VERSION 5.7 ;
  NOWIREEXTENSIONATPIN ON ;
  DIVIDERCHAR "/" ;
  BUSBITCHARS "[]" ;
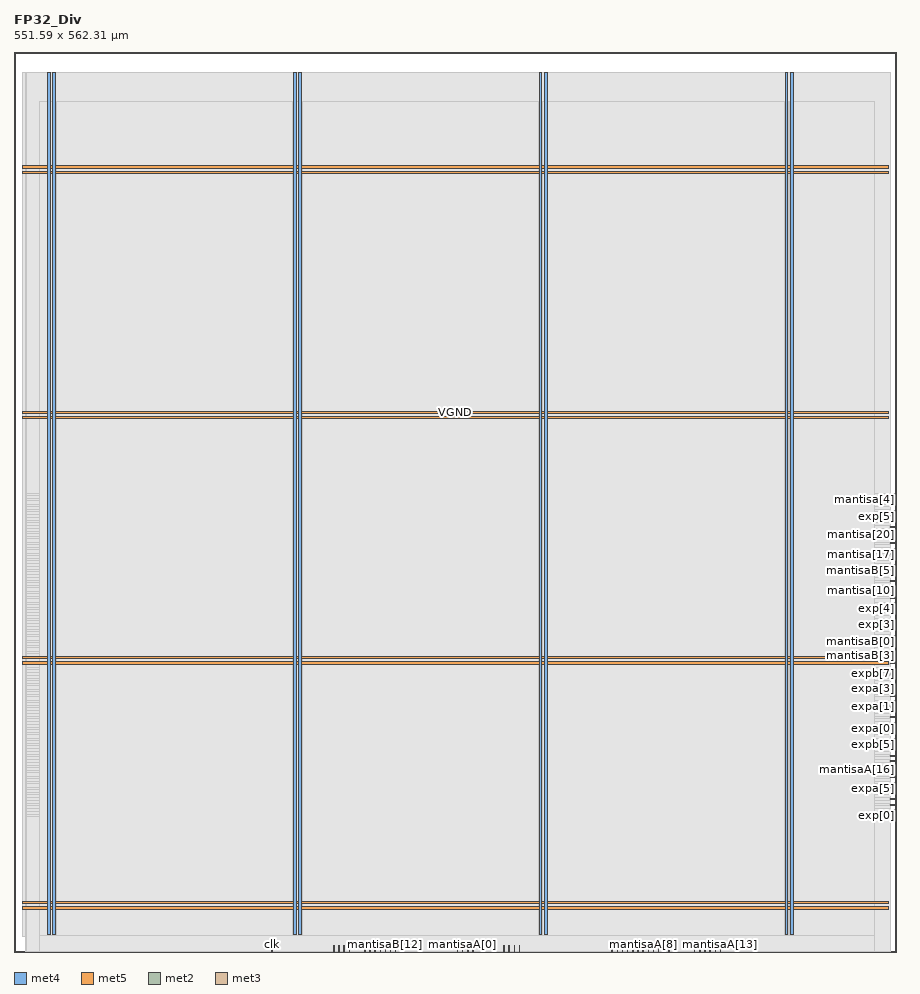
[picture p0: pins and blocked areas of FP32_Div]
MACRO FP32_Div
  CLASS BLOCK ;
  FOREIGN FP32_Div ;
  ORIGIN 0.000 0.000 ;
  SIZE 551.590 BY 562.310 ;
  PIN VGND
    DIRECTION INOUT ;
    USE GROUND ;
    PORT
      LAYER met4 ;
        RECT 24.340 10.640 25.940 549.680 ;
    END
    PORT
      LAYER met4 ;
        RECT 177.940 10.640 179.540 549.680 ;
    END
    PORT
      LAYER met4 ;
        RECT 331.540 10.640 333.140 549.680 ;
    END
    PORT
      LAYER met4 ;
        RECT 485.140 10.640 486.740 549.680 ;
    END
    PORT
      LAYER met5 ;
        RECT 5.280 30.030 546.260 31.630 ;
    END
    PORT
      LAYER met5 ;
        RECT 5.280 183.210 546.260 184.810 ;
    END
    PORT
      LAYER met5 ;
        RECT 5.280 336.390 546.260 337.990 ;
    END
    PORT
      LAYER met5 ;
        RECT 5.280 489.570 546.260 491.170 ;
    END
  END VGND
  PIN VPWR
    DIRECTION INOUT ;
    USE POWER ;
    PORT
      LAYER met4 ;
        RECT 21.040 10.640 22.640 549.680 ;
    END
    PORT
      LAYER met4 ;
        RECT 174.640 10.640 176.240 549.680 ;
    END
    PORT
      LAYER met4 ;
        RECT 328.240 10.640 329.840 549.680 ;
    END
    PORT
      LAYER met4 ;
        RECT 481.840 10.640 483.440 549.680 ;
    END
    PORT
      LAYER met5 ;
        RECT 5.280 26.730 546.260 28.330 ;
    END
    PORT
      LAYER met5 ;
        RECT 5.280 179.910 546.260 181.510 ;
    END
    PORT
      LAYER met5 ;
        RECT 5.280 333.090 546.260 334.690 ;
    END
    PORT
      LAYER met5 ;
        RECT 5.280 486.270 546.260 487.870 ;
    END
  END VPWR
  PIN clk
    DIRECTION INPUT ;
    USE SIGNAL ;
    ANTENNAGATEAREA 1.286700 ;
    ANTENNADIFFAREA 0.434700 ;
    PORT
      LAYER met2 ;
        RECT 161.090 0.000 161.370 4.000 ;
    END
  END clk
  PIN exp[0]
    DIRECTION OUTPUT ;
    USE SIGNAL ;
    ANTENNADIFFAREA 0.445500 ;
    PORT
      LAYER met3 ;
        RECT 547.590 85.040 551.590 85.640 ;
    END
  END exp[0]
  PIN exp[1]
    DIRECTION OUTPUT ;
    USE SIGNAL ;
    ANTENNADIFFAREA 0.445500 ;
    PORT
      LAYER met3 ;
        RECT 547.590 95.240 551.590 95.840 ;
    END
  END exp[1]
  PIN exp[2]
    DIRECTION OUTPUT ;
    USE SIGNAL ;
    ANTENNADIFFAREA 0.445500 ;
    PORT
      LAYER met3 ;
        RECT 547.590 285.640 551.590 286.240 ;
    END
  END exp[2]
  PIN exp[3]
    DIRECTION OUTPUT ;
    USE SIGNAL ;
    ANTENNADIFFAREA 0.445500 ;
    PORT
      LAYER met3 ;
        RECT 547.590 204.040 551.590 204.640 ;
    END
  END exp[3]
  PIN exp[4]
    DIRECTION OUTPUT ;
    USE SIGNAL ;
    ANTENNADIFFAREA 0.445500 ;
    PORT
      LAYER met3 ;
        RECT 547.590 214.240 551.590 214.840 ;
    END
  END exp[4]
  PIN exp[5]
    DIRECTION OUTPUT ;
    USE SIGNAL ;
    ANTENNADIFFAREA 0.445500 ;
    PORT
      LAYER met3 ;
        RECT 547.590 272.040 551.590 272.640 ;
    END
  END exp[5]
  PIN exp[6]
    DIRECTION OUTPUT ;
    USE SIGNAL ;
    ANTENNADIFFAREA 0.445500 ;
    PORT
      LAYER met3 ;
        RECT 547.590 258.440 551.590 259.040 ;
    END
  END exp[6]
  PIN exp[7]
    DIRECTION OUTPUT ;
    USE SIGNAL ;
    ANTENNADIFFAREA 0.445500 ;
    PORT
      LAYER met3 ;
        RECT 547.590 268.640 551.590 269.240 ;
    END
  END exp[7]
  PIN expa[0]
    DIRECTION INPUT ;
    USE SIGNAL ;
    ANTENNAGATEAREA 0.196500 ;
    PORT
      LAYER met3 ;
        RECT 547.590 139.440 551.590 140.040 ;
    END
  END expa[0]
  PIN expa[1]
    DIRECTION INPUT ;
    USE SIGNAL ;
    ANTENNAGATEAREA 0.196500 ;
    PORT
      LAYER met3 ;
        RECT 547.590 153.040 551.590 153.640 ;
    END
  END expa[1]
  PIN expa[2]
    DIRECTION INPUT ;
    USE SIGNAL ;
    ANTENNAGATEAREA 0.196500 ;
    PORT
      LAYER met3 ;
        RECT 547.590 149.640 551.590 150.240 ;
    END
  END expa[2]
  PIN expa[3]
    DIRECTION INPUT ;
    USE SIGNAL ;
    ANTENNAGATEAREA 0.126000 ;
    PORT
      LAYER met3 ;
        RECT 547.590 159.840 551.590 160.440 ;
    END
  END expa[3]
  PIN expa[4]
    DIRECTION INPUT ;
    USE SIGNAL ;
    ANTENNAGATEAREA 0.196500 ;
    PORT
      LAYER met3 ;
        RECT 547.590 105.440 551.590 106.040 ;
    END
  END expa[4]
  PIN expa[5]
    DIRECTION INPUT ;
    USE SIGNAL ;
    ANTENNAGATEAREA 0.126000 ;
    PORT
      LAYER met3 ;
        RECT 547.590 102.040 551.590 102.640 ;
    END
  END expa[5]
  PIN expa[6]
    DIRECTION INPUT ;
    USE SIGNAL ;
    ANTENNAGATEAREA 0.196500 ;
    PORT
      LAYER met3 ;
        RECT 547.590 98.640 551.590 99.240 ;
    END
  END expa[6]
  PIN expa[7]
    DIRECTION INPUT ;
    USE SIGNAL ;
    ANTENNAGATEAREA 0.196500 ;
    PORT
      LAYER met3 ;
        RECT 547.590 122.440 551.590 123.040 ;
    END
  END expa[7]
  PIN expb[0]
    DIRECTION INPUT ;
    USE SIGNAL ;
    ANTENNAGATEAREA 0.196500 ;
    PORT
      LAYER met3 ;
        RECT 547.590 156.440 551.590 157.040 ;
    END
  END expb[0]
  PIN expb[1]
    DIRECTION INPUT ;
    USE SIGNAL ;
    ANTENNAGATEAREA 0.196500 ;
    PORT
      LAYER met3 ;
        RECT 547.590 146.240 551.590 146.840 ;
    END
  END expb[1]
  PIN expb[2]
    DIRECTION INPUT ;
    USE SIGNAL ;
    ANTENNAGATEAREA 0.196500 ;
    PORT
      LAYER met3 ;
        RECT 547.590 142.840 551.590 143.440 ;
    END
  END expb[2]
  PIN expb[3]
    DIRECTION INPUT ;
    USE SIGNAL ;
    ANTENNAGATEAREA 0.126000 ;
    PORT
      LAYER met3 ;
        RECT 547.590 132.640 551.590 133.240 ;
    END
  END expb[3]
  PIN expb[4]
    DIRECTION INPUT ;
    USE SIGNAL ;
    ANTENNAGATEAREA 0.196500 ;
    PORT
      LAYER met3 ;
        RECT 547.590 163.240 551.590 163.840 ;
    END
  END expb[4]
  PIN expb[5]
    DIRECTION INPUT ;
    USE SIGNAL ;
    ANTENNAGATEAREA 0.196500 ;
    PORT
      LAYER met3 ;
        RECT 547.590 129.240 551.590 129.840 ;
    END
  END expb[5]
  PIN expb[6]
    DIRECTION INPUT ;
    USE SIGNAL ;
    ANTENNAGATEAREA 0.196500 ;
    PORT
      LAYER met3 ;
        RECT 547.590 125.840 551.590 126.440 ;
    END
  END expb[6]
  PIN expb[7]
    DIRECTION INPUT ;
    USE SIGNAL ;
    ANTENNAGATEAREA 0.196500 ;
    PORT
      LAYER met3 ;
        RECT 547.590 173.440 551.590 174.040 ;
    END
  END expb[7]
  PIN mantisaA[0]
    DIRECTION INPUT ;
    USE SIGNAL ;
    ANTENNAGATEAREA 0.196500 ;
    PORT
      LAYER met2 ;
        RECT 280.230 0.000 280.510 4.000 ;
    END
  END mantisaA[0]
  PIN mantisaA[10]
    DIRECTION INPUT ;
    USE SIGNAL ;
    ANTENNAGATEAREA 0.196500 ;
    PORT
      LAYER met2 ;
        RECT 402.590 0.000 402.870 4.000 ;
    END
  END mantisaA[10]
  PIN mantisaA[11]
    DIRECTION INPUT ;
    USE SIGNAL ;
    ANTENNAGATEAREA 0.196500 ;
    PORT
      LAYER met2 ;
        RECT 396.150 0.000 396.430 4.000 ;
    END
  END mantisaA[11]
  PIN mantisaA[12]
    DIRECTION INPUT ;
    USE SIGNAL ;
    ANTENNAGATEAREA 0.196500 ;
    PORT
      LAYER met2 ;
        RECT 431.570 0.000 431.850 4.000 ;
    END
  END mantisaA[12]
  PIN mantisaA[13]
    DIRECTION INPUT ;
    USE SIGNAL ;
    ANTENNAGATEAREA 0.196500 ;
    PORT
      LAYER met2 ;
        RECT 441.230 0.000 441.510 4.000 ;
    END
  END mantisaA[13]
  PIN mantisaA[14]
    DIRECTION INPUT ;
    USE SIGNAL ;
    ANTENNAGATEAREA 0.196500 ;
    PORT
      LAYER met2 ;
        RECT 434.790 0.000 435.070 4.000 ;
    END
  END mantisaA[14]
  PIN mantisaA[15]
    DIRECTION INPUT ;
    USE SIGNAL ;
    ANTENNAGATEAREA 0.196500 ;
    PORT
      LAYER met2 ;
        RECT 438.010 0.000 438.290 4.000 ;
    END
  END mantisaA[15]
  PIN mantisaA[16]
    DIRECTION INPUT ;
    USE SIGNAL ;
    ANTENNAGATEAREA 0.196500 ;
    PORT
      LAYER met3 ;
        RECT 547.590 108.840 551.590 109.440 ;
    END
  END mantisaA[16]
  PIN mantisaA[17]
    DIRECTION INPUT ;
    USE SIGNAL ;
    ANTENNAGATEAREA 0.196500 ;
    PORT
      LAYER met3 ;
        RECT 547.590 112.240 551.590 112.840 ;
    END
  END mantisaA[17]
  PIN mantisaA[18]
    DIRECTION INPUT ;
    USE SIGNAL ;
    ANTENNAGATEAREA 0.196500 ;
    PORT
      LAYER met3 ;
        RECT 547.590 119.040 551.590 119.640 ;
    END
  END mantisaA[18]
  PIN mantisaA[19]
    DIRECTION INPUT ;
    USE SIGNAL ;
    ANTENNAGATEAREA 0.196500 ;
    PORT
      LAYER met3 ;
        RECT 547.590 115.640 551.590 116.240 ;
    END
  END mantisaA[19]
  PIN mantisaA[1]
    DIRECTION INPUT ;
    USE SIGNAL ;
    ANTENNAGATEAREA 0.196500 ;
    PORT
      LAYER met2 ;
        RECT 277.010 0.000 277.290 4.000 ;
    END
  END mantisaA[1]
  PIN mantisaA[20]
    DIRECTION INPUT ;
    USE SIGNAL ;
    ANTENNAGATEAREA 0.196500 ;
    PORT
      LAYER met2 ;
        RECT 428.350 0.000 428.630 4.000 ;
    END
  END mantisaA[20]
  PIN mantisaA[21]
    DIRECTION INPUT ;
    USE SIGNAL ;
    ANTENNAGATEAREA 0.196500 ;
    PORT
      LAYER met2 ;
        RECT 425.130 0.000 425.410 4.000 ;
    END
  END mantisaA[21]
  PIN mantisaA[22]
    DIRECTION INPUT ;
    USE SIGNAL ;
    ANTENNAGATEAREA 0.196500 ;
    PORT
      LAYER met2 ;
        RECT 409.030 0.000 409.310 4.000 ;
    END
  END mantisaA[22]
  PIN mantisaA[2]
    DIRECTION INPUT ;
    USE SIGNAL ;
    ANTENNAGATEAREA 0.196500 ;
    PORT
      LAYER met2 ;
        RECT 286.670 0.000 286.950 4.000 ;
    END
  END mantisaA[2]
  PIN mantisaA[3]
    DIRECTION INPUT ;
    USE SIGNAL ;
    ANTENNAGATEAREA 0.196500 ;
    PORT
      LAYER met2 ;
        RECT 283.450 0.000 283.730 4.000 ;
    END
  END mantisaA[3]
  PIN mantisaA[4]
    DIRECTION INPUT ;
    USE SIGNAL ;
    ANTENNAGATEAREA 0.196500 ;
    PORT
      LAYER met2 ;
        RECT 305.990 0.000 306.270 4.000 ;
    END
  END mantisaA[4]
  PIN mantisaA[5]
    DIRECTION INPUT ;
    USE SIGNAL ;
    ANTENNAGATEAREA 0.196500 ;
    PORT
      LAYER met2 ;
        RECT 312.430 0.000 312.710 4.000 ;
    END
  END mantisaA[5]
  PIN mantisaA[6]
    DIRECTION INPUT ;
    USE SIGNAL ;
    ANTENNAGATEAREA 0.196500 ;
    PORT
      LAYER met2 ;
        RECT 309.210 0.000 309.490 4.000 ;
    END
  END mantisaA[6]
  PIN mantisaA[7]
    DIRECTION INPUT ;
    USE SIGNAL ;
    ANTENNAGATEAREA 0.196500 ;
    PORT
      LAYER met2 ;
        RECT 315.650 0.000 315.930 4.000 ;
    END
  END mantisaA[7]
  PIN mantisaA[8]
    DIRECTION INPUT ;
    USE SIGNAL ;
    ANTENNAGATEAREA 0.196500 ;
    PORT
      LAYER met2 ;
        RECT 392.930 0.000 393.210 4.000 ;
    END
  END mantisaA[8]
  PIN mantisaA[9]
    DIRECTION INPUT ;
    USE SIGNAL ;
    ANTENNAGATEAREA 0.196500 ;
    PORT
      LAYER met2 ;
        RECT 373.610 0.000 373.890 4.000 ;
    END
  END mantisaA[9]
  PIN mantisaB[0]
    DIRECTION INPUT ;
    USE SIGNAL ;
    ANTENNAGATEAREA 0.196500 ;
    PORT
      LAYER met3 ;
        RECT 547.590 193.840 551.590 194.440 ;
    END
  END mantisaB[0]
  PIN mantisaB[10]
    DIRECTION INPUT ;
    USE SIGNAL ;
    ANTENNAGATEAREA 0.196500 ;
    PORT
      LAYER met2 ;
        RECT 389.710 0.000 389.990 4.000 ;
    END
  END mantisaB[10]
  PIN mantisaB[11]
    DIRECTION INPUT ;
    USE SIGNAL ;
    ANTENNAGATEAREA 0.196500 ;
    PORT
      LAYER met2 ;
        RECT 386.490 0.000 386.770 4.000 ;
    END
  END mantisaB[11]
  PIN mantisaB[12]
    DIRECTION INPUT ;
    USE SIGNAL ;
    ANTENNAGATEAREA 0.196500 ;
    PORT
      LAYER met2 ;
        RECT 231.930 0.000 232.210 4.000 ;
    END
  END mantisaB[12]
  PIN mantisaB[13]
    DIRECTION INPUT ;
    USE SIGNAL ;
    ANTENNAGATEAREA 0.196500 ;
    PORT
      LAYER met2 ;
        RECT 228.710 0.000 228.990 4.000 ;
    END
  END mantisaB[13]
  PIN mantisaB[14]
    DIRECTION INPUT ;
    USE SIGNAL ;
    ANTENNAGATEAREA 0.196500 ;
    PORT
      LAYER met2 ;
        RECT 235.150 0.000 235.430 4.000 ;
    END
  END mantisaB[14]
  PIN mantisaB[15]
    DIRECTION INPUT ;
    USE SIGNAL ;
    ANTENNAGATEAREA 0.196500 ;
    PORT
      LAYER met2 ;
        RECT 238.370 0.000 238.650 4.000 ;
    END
  END mantisaB[15]
  PIN mantisaB[16]
    DIRECTION INPUT ;
    USE SIGNAL ;
    ANTENNAGATEAREA 0.196500 ;
    PORT
      LAYER met2 ;
        RECT 206.170 0.000 206.450 4.000 ;
    END
  END mantisaB[16]
  PIN mantisaB[17]
    DIRECTION INPUT ;
    USE SIGNAL ;
    ANTENNAGATEAREA 0.196500 ;
    PORT
      LAYER met2 ;
        RECT 209.390 0.000 209.670 4.000 ;
    END
  END mantisaB[17]
  PIN mantisaB[18]
    DIRECTION INPUT ;
    USE SIGNAL ;
    ANTENNAGATEAREA 0.196500 ;
    PORT
      LAYER met2 ;
        RECT 202.950 0.000 203.230 4.000 ;
    END
  END mantisaB[18]
  PIN mantisaB[19]
    DIRECTION INPUT ;
    USE SIGNAL ;
    ANTENNAGATEAREA 0.196500 ;
    PORT
      LAYER met2 ;
        RECT 199.730 0.000 200.010 4.000 ;
    END
  END mantisaB[19]
  PIN mantisaB[1]
    DIRECTION INPUT ;
    USE SIGNAL ;
    ANTENNAGATEAREA 0.196500 ;
    PORT
      LAYER met3 ;
        RECT 547.590 197.240 551.590 197.840 ;
    END
  END mantisaB[1]
  PIN mantisaB[20]
    DIRECTION INPUT ;
    USE SIGNAL ;
    ANTENNAGATEAREA 0.196500 ;
    PORT
      LAYER met2 ;
        RECT 219.050 0.000 219.330 4.000 ;
    END
  END mantisaB[20]
  PIN mantisaB[21]
    DIRECTION INPUT ;
    USE SIGNAL ;
    ANTENNAGATEAREA 0.196500 ;
    PORT
      LAYER met2 ;
        RECT 225.490 0.000 225.770 4.000 ;
    END
  END mantisaB[21]
  PIN mantisaB[22]
    DIRECTION INPUT ;
    USE SIGNAL ;
    ANTENNAGATEAREA 0.196500 ;
    PORT
      LAYER met2 ;
        RECT 222.270 0.000 222.550 4.000 ;
    END
  END mantisaB[22]
  PIN mantisaB[2]
    DIRECTION INPUT ;
    USE SIGNAL ;
    ANTENNAGATEAREA 0.196500 ;
    PORT
      LAYER met3 ;
        RECT 547.590 88.440 551.590 89.040 ;
    END
  END mantisaB[2]
  PIN mantisaB[3]
    DIRECTION INPUT ;
    USE SIGNAL ;
    ANTENNAGATEAREA 0.196500 ;
    PORT
      LAYER met3 ;
        RECT 547.590 180.240 551.590 180.840 ;
    END
  END mantisaB[3]
  PIN mantisaB[4]
    DIRECTION INPUT ;
    USE SIGNAL ;
    ANTENNAGATEAREA 0.196500 ;
    PORT
      LAYER met3 ;
        RECT 547.590 200.640 551.590 201.240 ;
    END
  END mantisaB[4]
  PIN mantisaB[5]
    DIRECTION INPUT ;
    USE SIGNAL ;
    ANTENNAGATEAREA 0.196500 ;
    PORT
      LAYER met3 ;
        RECT 547.590 238.040 551.590 238.640 ;
    END
  END mantisaB[5]
  PIN mantisaB[6]
    DIRECTION INPUT ;
    USE SIGNAL ;
    ANTENNAGATEAREA 0.196500 ;
    PORT
      LAYER met3 ;
        RECT 547.590 187.040 551.590 187.640 ;
    END
  END mantisaB[6]
  PIN mantisaB[7]
    DIRECTION INPUT ;
    USE SIGNAL ;
    ANTENNAGATEAREA 0.196500 ;
    PORT
      LAYER met3 ;
        RECT 547.590 91.840 551.590 92.440 ;
    END
  END mantisaB[7]
  PIN mantisaB[8]
    DIRECTION INPUT ;
    USE SIGNAL ;
    ANTENNAGATEAREA 0.196500 ;
    PORT
      LAYER met2 ;
        RECT 380.050 0.000 380.330 4.000 ;
    END
  END mantisaB[8]
  PIN mantisaB[9]
    DIRECTION INPUT ;
    USE SIGNAL ;
    ANTENNAGATEAREA 0.196500 ;
    PORT
      LAYER met2 ;
        RECT 399.370 0.000 399.650 4.000 ;
    END
  END mantisaB[9]
  PIN mantisa[0]
    DIRECTION OUTPUT ;
    USE SIGNAL ;
    ANTENNADIFFAREA 0.445500 ;
    PORT
      LAYER met3 ;
        RECT 547.590 278.840 551.590 279.440 ;
    END
  END mantisa[0]
  PIN mantisa[10]
    DIRECTION OUTPUT ;
    USE SIGNAL ;
    ANTENNADIFFAREA 0.445500 ;
    PORT
      LAYER met3 ;
        RECT 547.590 221.040 551.590 221.640 ;
    END
  END mantisa[10]
  PIN mantisa[11]
    DIRECTION OUTPUT ;
    USE SIGNAL ;
    ANTENNADIFFAREA 0.445500 ;
    PORT
      LAYER met3 ;
        RECT 547.590 234.640 551.590 235.240 ;
    END
  END mantisa[11]
  PIN mantisa[12]
    DIRECTION OUTPUT ;
    USE SIGNAL ;
    ANTENNADIFFAREA 0.445500 ;
    PORT
      LAYER met3 ;
        RECT 547.590 261.840 551.590 262.440 ;
    END
  END mantisa[12]
  PIN mantisa[13]
    DIRECTION OUTPUT ;
    USE SIGNAL ;
    ANTENNADIFFAREA 0.445500 ;
    PORT
      LAYER met3 ;
        RECT 547.590 241.440 551.590 242.040 ;
    END
  END mantisa[13]
  PIN mantisa[14]
    DIRECTION OUTPUT ;
    USE SIGNAL ;
    ANTENNADIFFAREA 0.445500 ;
    PORT
      LAYER met3 ;
        RECT 547.590 217.640 551.590 218.240 ;
    END
  END mantisa[14]
  PIN mantisa[15]
    DIRECTION OUTPUT ;
    USE SIGNAL ;
    ANTENNADIFFAREA 0.445500 ;
    PORT
      LAYER met3 ;
        RECT 547.590 176.840 551.590 177.440 ;
    END
  END mantisa[15]
  PIN mantisa[16]
    DIRECTION OUTPUT ;
    USE SIGNAL ;
    ANTENNADIFFAREA 0.445500 ;
    PORT
      LAYER met3 ;
        RECT 547.590 224.440 551.590 225.040 ;
    END
  END mantisa[16]
  PIN mantisa[17]
    DIRECTION OUTPUT ;
    USE SIGNAL ;
    ANTENNADIFFAREA 0.445500 ;
    PORT
      LAYER met3 ;
        RECT 547.590 248.240 551.590 248.840 ;
    END
  END mantisa[17]
  PIN mantisa[18]
    DIRECTION OUTPUT ;
    USE SIGNAL ;
    ANTENNADIFFAREA 0.445500 ;
    PORT
      LAYER met3 ;
        RECT 547.590 207.440 551.590 208.040 ;
    END
  END mantisa[18]
  PIN mantisa[19]
    DIRECTION OUTPUT ;
    USE SIGNAL ;
    ANTENNADIFFAREA 0.445500 ;
    PORT
      LAYER met3 ;
        RECT 547.590 183.640 551.590 184.240 ;
    END
  END mantisa[19]
  PIN mantisa[1]
    DIRECTION OUTPUT ;
    USE SIGNAL ;
    ANTENNADIFFAREA 0.445500 ;
    PORT
      LAYER met3 ;
        RECT 547.590 251.640 551.590 252.240 ;
    END
  END mantisa[1]
  PIN mantisa[20]
    DIRECTION OUTPUT ;
    USE SIGNAL ;
    ANTENNADIFFAREA 0.445500 ;
    PORT
      LAYER met3 ;
        RECT 547.590 265.240 551.590 265.840 ;
    END
  END mantisa[20]
  PIN mantisa[21]
    DIRECTION OUTPUT ;
    USE SIGNAL ;
    ANTENNADIFFAREA 0.445500 ;
    PORT
      LAYER met2 ;
        RECT 383.270 0.000 383.550 4.000 ;
    END
  END mantisa[21]
  PIN mantisa[22]
    DIRECTION OUTPUT ;
    USE SIGNAL ;
    ANTENNADIFFAREA 0.445500 ;
    PORT
      LAYER met2 ;
        RECT 376.830 0.000 377.110 4.000 ;
    END
  END mantisa[22]
  PIN mantisa[2]
    DIRECTION OUTPUT ;
    USE SIGNAL ;
    ANTENNADIFFAREA 0.445500 ;
    PORT
      LAYER met3 ;
        RECT 547.590 210.840 551.590 211.440 ;
    END
  END mantisa[2]
  PIN mantisa[3]
    DIRECTION OUTPUT ;
    USE SIGNAL ;
    ANTENNADIFFAREA 0.445500 ;
    PORT
      LAYER met3 ;
        RECT 547.590 244.840 551.590 245.440 ;
    END
  END mantisa[3]
  PIN mantisa[4]
    DIRECTION OUTPUT ;
    USE SIGNAL ;
    ANTENNADIFFAREA 0.445500 ;
    PORT
      LAYER met3 ;
        RECT 547.590 282.240 551.590 282.840 ;
    END
  END mantisa[4]
  PIN mantisa[5]
    DIRECTION OUTPUT ;
    USE SIGNAL ;
    ANTENNADIFFAREA 0.445500 ;
    PORT
      LAYER met3 ;
        RECT 547.590 227.840 551.590 228.440 ;
    END
  END mantisa[5]
  PIN mantisa[6]
    DIRECTION OUTPUT ;
    USE SIGNAL ;
    ANTENNADIFFAREA 0.445500 ;
    PORT
      LAYER met3 ;
        RECT 547.590 190.440 551.590 191.040 ;
    END
  END mantisa[6]
  PIN mantisa[7]
    DIRECTION OUTPUT ;
    USE SIGNAL ;
    ANTENNADIFFAREA 0.445500 ;
    PORT
      LAYER met3 ;
        RECT 547.590 255.040 551.590 255.640 ;
    END
  END mantisa[7]
  PIN mantisa[8]
    DIRECTION OUTPUT ;
    USE SIGNAL ;
    ANTENNADIFFAREA 0.445500 ;
    PORT
      LAYER met3 ;
        RECT 547.590 275.440 551.590 276.040 ;
    END
  END mantisa[8]
  PIN mantisa[9]
    DIRECTION OUTPUT ;
    USE SIGNAL ;
    ANTENNADIFFAREA 0.445500 ;
    PORT
      LAYER met3 ;
        RECT 547.590 231.240 551.590 231.840 ;
    END
  END mantisa[9]
  PIN sign
    DIRECTION OUTPUT ;
    USE SIGNAL ;
    ANTENNADIFFAREA 0.445500 ;
    PORT
      LAYER met3 ;
        RECT 547.590 170.040 551.590 170.640 ;
    END
  END sign
  PIN signa
    DIRECTION INPUT ;
    USE SIGNAL ;
    ANTENNAGATEAREA 0.196500 ;
    PORT
      LAYER met3 ;
        RECT 547.590 166.640 551.590 167.240 ;
    END
  END signa
  PIN signb
    DIRECTION INPUT ;
    USE SIGNAL ;
    ANTENNAGATEAREA 0.196500 ;
    PORT
      LAYER met3 ;
        RECT 547.590 136.040 551.590 136.640 ;
    END
  END signb
  OBS
      LAYER nwell ;
        RECT 5.330 10.795 546.210 549.525 ;
      LAYER li1 ;
        RECT 5.520 10.795 546.020 549.525 ;
      LAYER met1 ;
        RECT 5.520 9.900 546.410 549.680 ;
      LAYER met2 ;
        RECT 7.460 4.280 546.390 549.625 ;
        RECT 7.460 0.155 160.810 4.280 ;
        RECT 161.650 0.155 199.450 4.280 ;
        RECT 200.290 0.155 202.670 4.280 ;
        RECT 203.510 0.155 205.890 4.280 ;
        RECT 206.730 0.155 209.110 4.280 ;
        RECT 209.950 0.155 218.770 4.280 ;
        RECT 219.610 0.155 221.990 4.280 ;
        RECT 222.830 0.155 225.210 4.280 ;
        RECT 226.050 0.155 228.430 4.280 ;
        RECT 229.270 0.155 231.650 4.280 ;
        RECT 232.490 0.155 234.870 4.280 ;
        RECT 235.710 0.155 238.090 4.280 ;
        RECT 238.930 0.155 276.730 4.280 ;
        RECT 277.570 0.155 279.950 4.280 ;
        RECT 280.790 0.155 283.170 4.280 ;
        RECT 284.010 0.155 286.390 4.280 ;
        RECT 287.230 0.155 305.710 4.280 ;
        RECT 306.550 0.155 308.930 4.280 ;
        RECT 309.770 0.155 312.150 4.280 ;
        RECT 312.990 0.155 315.370 4.280 ;
        RECT 316.210 0.155 373.330 4.280 ;
        RECT 374.170 0.155 376.550 4.280 ;
        RECT 377.390 0.155 379.770 4.280 ;
        RECT 380.610 0.155 382.990 4.280 ;
        RECT 383.830 0.155 386.210 4.280 ;
        RECT 387.050 0.155 389.430 4.280 ;
        RECT 390.270 0.155 392.650 4.280 ;
        RECT 393.490 0.155 395.870 4.280 ;
        RECT 396.710 0.155 399.090 4.280 ;
        RECT 399.930 0.155 402.310 4.280 ;
        RECT 403.150 0.155 408.750 4.280 ;
        RECT 409.590 0.155 424.850 4.280 ;
        RECT 425.690 0.155 428.070 4.280 ;
        RECT 428.910 0.155 431.290 4.280 ;
        RECT 432.130 0.155 434.510 4.280 ;
        RECT 435.350 0.155 437.730 4.280 ;
        RECT 438.570 0.155 440.950 4.280 ;
        RECT 441.790 0.155 546.390 4.280 ;
      LAYER met3 ;
        RECT 7.885 286.640 547.590 549.605 ;
        RECT 7.885 285.240 547.190 286.640 ;
        RECT 7.885 283.240 547.590 285.240 ;
        RECT 7.885 281.840 547.190 283.240 ;
        RECT 7.885 279.840 547.590 281.840 ;
        RECT 7.885 278.440 547.190 279.840 ;
        RECT 7.885 276.440 547.590 278.440 ;
        RECT 7.885 275.040 547.190 276.440 ;
        RECT 7.885 273.040 547.590 275.040 ;
        RECT 7.885 271.640 547.190 273.040 ;
        RECT 7.885 269.640 547.590 271.640 ;
        RECT 7.885 268.240 547.190 269.640 ;
        RECT 7.885 266.240 547.590 268.240 ;
        RECT 7.885 264.840 547.190 266.240 ;
        RECT 7.885 262.840 547.590 264.840 ;
        RECT 7.885 261.440 547.190 262.840 ;
        RECT 7.885 259.440 547.590 261.440 ;
        RECT 7.885 258.040 547.190 259.440 ;
        RECT 7.885 256.040 547.590 258.040 ;
        RECT 7.885 254.640 547.190 256.040 ;
        RECT 7.885 252.640 547.590 254.640 ;
        RECT 7.885 251.240 547.190 252.640 ;
        RECT 7.885 249.240 547.590 251.240 ;
        RECT 7.885 247.840 547.190 249.240 ;
        RECT 7.885 245.840 547.590 247.840 ;
        RECT 7.885 244.440 547.190 245.840 ;
        RECT 7.885 242.440 547.590 244.440 ;
        RECT 7.885 241.040 547.190 242.440 ;
        RECT 7.885 239.040 547.590 241.040 ;
        RECT 7.885 237.640 547.190 239.040 ;
        RECT 7.885 235.640 547.590 237.640 ;
        RECT 7.885 234.240 547.190 235.640 ;
        RECT 7.885 232.240 547.590 234.240 ;
        RECT 7.885 230.840 547.190 232.240 ;
        RECT 7.885 228.840 547.590 230.840 ;
        RECT 7.885 227.440 547.190 228.840 ;
        RECT 7.885 225.440 547.590 227.440 ;
        RECT 7.885 224.040 547.190 225.440 ;
        RECT 7.885 222.040 547.590 224.040 ;
        RECT 7.885 220.640 547.190 222.040 ;
        RECT 7.885 218.640 547.590 220.640 ;
        RECT 7.885 217.240 547.190 218.640 ;
        RECT 7.885 215.240 547.590 217.240 ;
        RECT 7.885 213.840 547.190 215.240 ;
        RECT 7.885 211.840 547.590 213.840 ;
        RECT 7.885 210.440 547.190 211.840 ;
        RECT 7.885 208.440 547.590 210.440 ;
        RECT 7.885 207.040 547.190 208.440 ;
        RECT 7.885 205.040 547.590 207.040 ;
        RECT 7.885 203.640 547.190 205.040 ;
        RECT 7.885 201.640 547.590 203.640 ;
        RECT 7.885 200.240 547.190 201.640 ;
        RECT 7.885 198.240 547.590 200.240 ;
        RECT 7.885 196.840 547.190 198.240 ;
        RECT 7.885 194.840 547.590 196.840 ;
        RECT 7.885 193.440 547.190 194.840 ;
        RECT 7.885 191.440 547.590 193.440 ;
        RECT 7.885 190.040 547.190 191.440 ;
        RECT 7.885 188.040 547.590 190.040 ;
        RECT 7.885 186.640 547.190 188.040 ;
        RECT 7.885 184.640 547.590 186.640 ;
        RECT 7.885 183.240 547.190 184.640 ;
        RECT 7.885 181.240 547.590 183.240 ;
        RECT 7.885 179.840 547.190 181.240 ;
        RECT 7.885 177.840 547.590 179.840 ;
        RECT 7.885 176.440 547.190 177.840 ;
        RECT 7.885 174.440 547.590 176.440 ;
        RECT 7.885 173.040 547.190 174.440 ;
        RECT 7.885 171.040 547.590 173.040 ;
        RECT 7.885 169.640 547.190 171.040 ;
        RECT 7.885 167.640 547.590 169.640 ;
        RECT 7.885 166.240 547.190 167.640 ;
        RECT 7.885 164.240 547.590 166.240 ;
        RECT 7.885 162.840 547.190 164.240 ;
        RECT 7.885 160.840 547.590 162.840 ;
        RECT 7.885 159.440 547.190 160.840 ;
        RECT 7.885 157.440 547.590 159.440 ;
        RECT 7.885 156.040 547.190 157.440 ;
        RECT 7.885 154.040 547.590 156.040 ;
        RECT 7.885 152.640 547.190 154.040 ;
        RECT 7.885 150.640 547.590 152.640 ;
        RECT 7.885 149.240 547.190 150.640 ;
        RECT 7.885 147.240 547.590 149.240 ;
        RECT 7.885 145.840 547.190 147.240 ;
        RECT 7.885 143.840 547.590 145.840 ;
        RECT 7.885 142.440 547.190 143.840 ;
        RECT 7.885 140.440 547.590 142.440 ;
        RECT 7.885 139.040 547.190 140.440 ;
        RECT 7.885 137.040 547.590 139.040 ;
        RECT 7.885 135.640 547.190 137.040 ;
        RECT 7.885 133.640 547.590 135.640 ;
        RECT 7.885 132.240 547.190 133.640 ;
        RECT 7.885 130.240 547.590 132.240 ;
        RECT 7.885 128.840 547.190 130.240 ;
        RECT 7.885 126.840 547.590 128.840 ;
        RECT 7.885 125.440 547.190 126.840 ;
        RECT 7.885 123.440 547.590 125.440 ;
        RECT 7.885 122.040 547.190 123.440 ;
        RECT 7.885 120.040 547.590 122.040 ;
        RECT 7.885 118.640 547.190 120.040 ;
        RECT 7.885 116.640 547.590 118.640 ;
        RECT 7.885 115.240 547.190 116.640 ;
        RECT 7.885 113.240 547.590 115.240 ;
        RECT 7.885 111.840 547.190 113.240 ;
        RECT 7.885 109.840 547.590 111.840 ;
        RECT 7.885 108.440 547.190 109.840 ;
        RECT 7.885 106.440 547.590 108.440 ;
        RECT 7.885 105.040 547.190 106.440 ;
        RECT 7.885 103.040 547.590 105.040 ;
        RECT 7.885 101.640 547.190 103.040 ;
        RECT 7.885 99.640 547.590 101.640 ;
        RECT 7.885 98.240 547.190 99.640 ;
        RECT 7.885 96.240 547.590 98.240 ;
        RECT 7.885 94.840 547.190 96.240 ;
        RECT 7.885 92.840 547.590 94.840 ;
        RECT 7.885 91.440 547.190 92.840 ;
        RECT 7.885 89.440 547.590 91.440 ;
        RECT 7.885 88.040 547.190 89.440 ;
        RECT 7.885 86.040 547.590 88.040 ;
        RECT 7.885 84.640 547.190 86.040 ;
        RECT 7.885 0.175 547.590 84.640 ;
      LAYER met4 ;
        RECT 15.935 10.240 20.640 531.585 ;
        RECT 23.040 10.240 23.940 531.585 ;
        RECT 26.340 10.240 174.240 531.585 ;
        RECT 176.640 10.240 177.540 531.585 ;
        RECT 179.940 10.240 327.840 531.585 ;
        RECT 330.240 10.240 331.140 531.585 ;
        RECT 333.540 10.240 481.440 531.585 ;
        RECT 483.840 10.240 484.740 531.585 ;
        RECT 487.140 10.240 537.905 531.585 ;
        RECT 15.935 0.175 537.905 10.240 ;
  END
END FP32_Div
END LIBRARY

